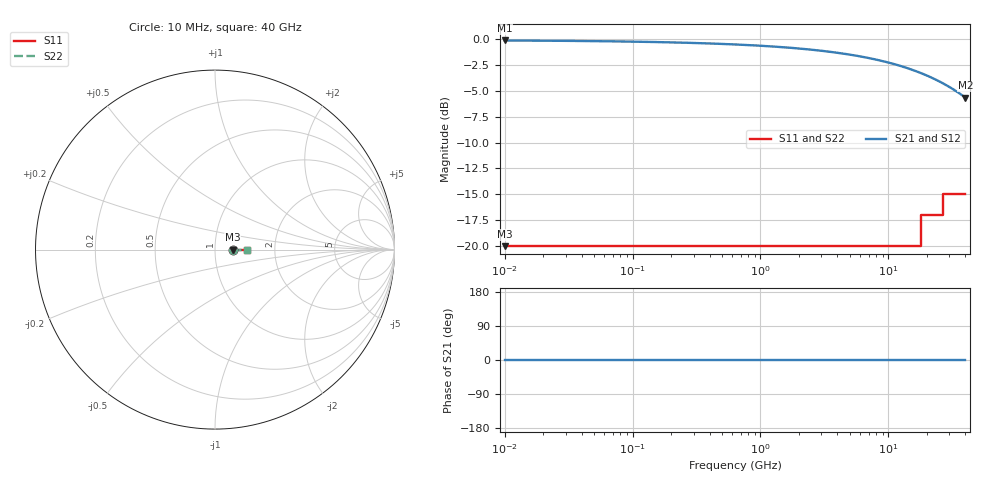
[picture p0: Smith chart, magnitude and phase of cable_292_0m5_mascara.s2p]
! CAL-ELEKTRA — ESPECIFICACIÓN SINTÉTICA DE EJEMPLO: no es la de ningún fabricante.
! Cable 2,92 mm de 0,5 m: S21/S12 = pérdidas de inserción máximas; S11/S22 = pérdidas de retorno mínimas
# GHZ S DB R 50
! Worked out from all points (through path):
!   304 points, 10 MHz to 40 GHz, reference 50 ohm
!   highest |S21| = -0.15 dB at 10 MHz (marker M1); lowest = -5.7 dB at 40 GHz (marker M2)
!   lowest |S11| = -20.0 dB at 10 MHz (marker M3), VSWR 1.22, Z = 61.1 + j0 ohm
!   |S11| at or under -10 dB: start of sweep to end of sweep
!   |S22| runs from -20.0 to -15.0 dB; largest |S21 - S12| = 0
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0.01  -20.00 0.0  -0.15 0.0  -0.15 0.0  -20.00 0.0
0.04002683  -20.00 0.0  -0.20 0.0  -0.20 0.0  -20.00 0.0
0.0846488  -20.00 0.0  -0.25 0.0  -0.25 0.0  -20.00 0.0
0.1602147  -20.00 0.0  -0.31 0.0  -0.31 0.0  -20.00 0.0
0.3388223  -20.00 0.0  -0.41 0.0  -0.41 0.0  -20.00 0.0
0.6412886  -20.00 0.0  -0.54 0.0  -0.54 0.0  -20.00 0.0
0.9456095  -20.00 0.0  -0.64 0.0  -0.64 0.0  -20.00 0.0
1.356198  -20.00 0.0  -0.76 0.0  -0.76 0.0  -20.00 0.0
1.891853  -20.00 0.0  -0.90 0.0  -0.90 0.0  -20.00 0.0
2.566875  -20.00 0.0  -1.06 0.0  -1.06 0.0  -20.00 0.0
3.784975  -20.00 0.0  -1.30 0.0  -1.30 0.0  -20.00 0.0
5.428431  -20.00 0.0  -1.59 0.0  -1.59 0.0  -20.00 0.0
7.572488  -20.00 0.0  -1.93 0.0  -1.93 0.0  -20.00 0.0
10.27439  -20.00 0.0  -2.32 0.0  -2.32 0.0  -20.00 0.0
13.55895  -20.00 0.0  -2.75 0.0  -2.75 0.0  -20.00 0.0
18  -20.00 0.0  -3.30 0.0  -3.30 0.0  -20.00 0.0
18  -17.00 0.0  -3.30 0.0  -3.30 0.0  -17.00 0.0
21.72829  -17.00 0.0  -3.73 0.0  -3.73 0.0  -17.00 0.0
26.5  -17.00 0.0  -4.26 0.0  -4.26 0.0  -17.00 0.0
26.5  -15.00 0.0  -4.26 0.0  -4.26 0.0  -15.00 0.0
32.94055  -15.00 0.0  -4.95 0.0  -4.95 0.0  -15.00 0.0
40  -15.00 0.0  -5.66 0.0  -5.66 0.0  -15.00 0.0
